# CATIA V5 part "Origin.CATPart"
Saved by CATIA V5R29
Part number: Origin
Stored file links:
  C:\Users\Administrator\Desktop\10-14 작업\stopper\Origin.CATPart

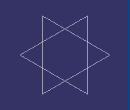
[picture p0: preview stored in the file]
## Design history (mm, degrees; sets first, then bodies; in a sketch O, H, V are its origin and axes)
Body1 (main body)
